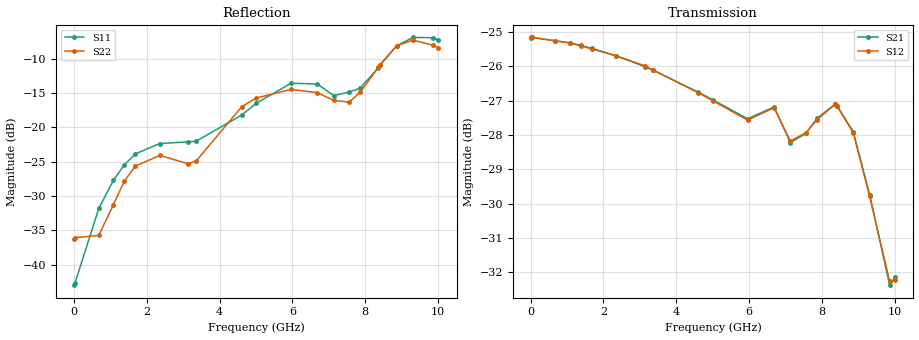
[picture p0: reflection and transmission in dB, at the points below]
! Device ID: PE43704
! Dir: z:\PE43704\PE43704_Char_1_20130516\PE43704\AMB\3p400V\24p25dB
! Serial: 14
! Insertion: A
! Impedance: 50 ohm
! Temp: Amb
! VDD: 3.400V
! Attenuation Step: 24.25dB
! IDD: 1.140292e-01mA
#  Hz  S  RI  R  50
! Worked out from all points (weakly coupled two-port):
!   401 points, 10 MHz to 10.01 GHz, reference 50 ohm
!   highest |S21| = -25.16 dB at 35 MHz (marker M1); lowest = -32.4 dB at 9.86 GHz (marker M2)
!   lowest |S11| = -43.0 dB at 10 MHz (marker M3), VSWR 1.01, Z = 50.7 + j0.044 ohm
!   |S11| at or under -10 dB: start of sweep to 8.533 GHz
!   |S22| runs from -36.3 to -7.2 dB; largest |S21 - S12| = 0.0006
!   S11 on the Smith chart (normalised r, x): 10 MHz: 1.01, +0.00; 4.61 GHz: 0.79, +0.08; 8.41 GHz: 0.78, +0.48; 9.31 GHz: 0.51, +0.54; 10.01 GHz: 0.45, +0.33
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1e7  0.00708 0.000434  0.0551 -0.000153  0.0552 -0.000129  0.0155 0.000248
3.5e7  0.00722 0.00156  0.0552 -0.000533  0.0552 -0.000541  0.0157 0.00107
6.85e8  -0.0108 0.0233  0.0537 -0.00967  0.0537 -0.00963  -0.00208 0.0162
1.085e9  -0.0335 0.0238  0.0521 -0.0149  0.0521 -0.0149  -0.0242 0.0126
1.385e9  -0.0505 0.0173  0.0504 -0.0186  0.0503 -0.0186  -0.0404 0.00374
1.685e9  -0.0637 0.00771  0.0484 -0.0221  0.0483 -0.0221  -0.0516 -0.0082
2.36e9  -0.0753 -0.0127  0.043 -0.029  0.043 -0.029  -0.0573 -0.0251
3.135e9  -0.0771 -0.0151  0.0357 -0.0351  0.0358 -0.0352  -0.053 -0.0124
3.36e9  -0.0789 -0.00897  0.0334 -0.0365  0.0334 -0.0365  -0.0569 -0.00333
4.61e9  -0.1118 0.0521  0.0211 -0.0408  0.0211 -0.0407  -0.1278 0.0614
5.01e9  -0.1309 0.0738  0.0182 -0.0409  0.0181 -0.0408  -0.1501 0.0661
5.96e9  -0.1812 0.1065  0.0101 -0.0408  0.0101 -0.0406  -0.1727 0.0779
6.685e9  -0.1811 0.1012  0.00533 -0.0434  0.00523 -0.0433  -0.1569 0.087
7.135e9  -0.148 0.0849  -0.000434 -0.0388  -0.000593 -0.039  -0.1148 0.1077
7.56e9  -0.1224 0.1337  -0.000766 -0.04  -0.00077 -0.0401  -0.0732 0.1344
7.86e9  -0.0857 0.1733  -0.0024 -0.042  -0.00229 -0.0418  -0.0597 0.1705
8.36e9  -0.0499 0.2681  -0.0116 -0.0426  -0.0115 -0.0426  -0.0662 0.2662
8.41e9  -0.0506 0.2813  -0.0129 -0.042  -0.0124 -0.0421  -0.0713 0.2782
8.86e9  -0.0892 0.3827  -0.0197 -0.0351  -0.0196 -0.035  -0.1203 0.3756
9.31e9  -0.1699 0.4207  -0.019 -0.0265  -0.0188 -0.0264  -0.1943 0.3875
9.86e9  -0.2883 0.3465  -0.00931 -0.0222  -0.00963 -0.0224  -0.295 0.268
1.001e10  -0.3132 0.3028  -0.00605 -0.024  -0.00611 -0.0237  -0.3126 0.2156
